VERSION 5.7 ;
  NOWIREEXTENSIONATPIN ON ;
  DIVIDERCHAR "/" ;
  BUSBITCHARS "[]" ;
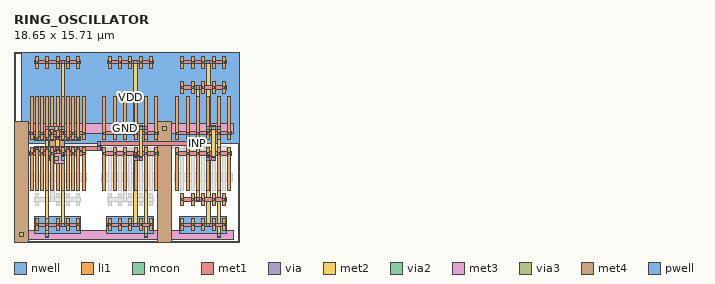
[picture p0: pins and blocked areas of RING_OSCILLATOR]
MACRO RING_OSCILLATOR
  CLASS BLOCK ;
  FOREIGN RING_OSCILLATOR ;
  ORIGIN 0.000 0.000 ;
  SIZE 18.650 BY 15.710 ;
  PIN VDD
    ANTENNADIFFAREA 7.014000 ;
    PORT
      LAYER nwell ;
        RECT 0.590 8.150 18.650 15.710 ;
      LAYER li1 ;
        RECT 1.755 14.365 2.005 15.375 ;
        RECT 2.615 14.365 2.865 15.375 ;
        RECT 3.475 14.365 3.725 15.375 ;
        RECT 4.335 14.365 4.585 15.375 ;
        RECT 5.195 14.365 5.445 15.375 ;
        RECT 7.775 14.365 8.025 15.375 ;
        RECT 8.635 14.365 8.885 15.375 ;
        RECT 9.495 14.365 9.745 15.375 ;
        RECT 10.355 14.365 10.605 15.375 ;
        RECT 11.215 14.365 11.465 15.375 ;
        RECT 13.795 14.365 14.045 15.375 ;
        RECT 14.655 14.365 14.905 15.375 ;
        RECT 15.515 14.365 15.765 15.375 ;
        RECT 16.375 14.365 16.625 15.375 ;
        RECT 17.235 14.365 17.485 15.375 ;
        RECT 1.325 8.485 1.575 12.015 ;
        RECT 2.185 8.485 2.435 12.015 ;
        RECT 3.045 8.485 3.295 12.015 ;
        RECT 3.905 8.485 4.155 12.015 ;
        RECT 4.765 8.485 5.015 12.015 ;
        RECT 5.625 8.485 5.875 12.015 ;
        RECT 7.345 8.485 7.595 12.015 ;
        RECT 8.205 8.485 8.455 12.015 ;
        RECT 9.065 8.485 9.315 12.015 ;
        RECT 9.925 8.485 10.175 12.015 ;
        RECT 10.785 8.485 11.035 12.015 ;
        RECT 11.645 8.485 11.895 12.015 ;
        RECT 13.365 8.485 13.615 12.015 ;
        RECT 14.225 8.485 14.475 12.015 ;
        RECT 15.085 8.485 15.335 12.015 ;
        RECT 15.945 8.485 16.195 12.015 ;
        RECT 16.805 8.485 17.055 12.015 ;
        RECT 17.665 8.485 17.915 12.015 ;
      LAYER mcon ;
        RECT 1.795 14.785 1.965 14.955 ;
        RECT 2.655 14.785 2.825 14.955 ;
        RECT 3.515 14.785 3.685 14.955 ;
        RECT 4.375 14.785 4.545 14.955 ;
        RECT 5.235 14.785 5.405 14.955 ;
        RECT 7.815 14.785 7.985 14.955 ;
        RECT 8.675 14.785 8.845 14.955 ;
        RECT 9.535 14.785 9.705 14.955 ;
        RECT 10.395 14.785 10.565 14.955 ;
        RECT 11.255 14.785 11.425 14.955 ;
        RECT 13.835 14.785 14.005 14.955 ;
        RECT 14.695 14.785 14.865 14.955 ;
        RECT 15.555 14.785 15.725 14.955 ;
        RECT 16.415 14.785 16.585 14.955 ;
        RECT 17.275 14.785 17.445 14.955 ;
        RECT 1.365 8.905 1.535 9.075 ;
        RECT 2.225 8.905 2.395 9.075 ;
        RECT 3.085 8.905 3.255 9.075 ;
        RECT 3.945 8.905 4.115 9.075 ;
        RECT 4.805 8.905 4.975 9.075 ;
        RECT 5.665 8.905 5.835 9.075 ;
        RECT 7.385 8.905 7.555 9.075 ;
        RECT 8.245 8.905 8.415 9.075 ;
        RECT 9.105 8.905 9.275 9.075 ;
        RECT 9.965 8.905 10.135 9.075 ;
        RECT 10.825 8.905 10.995 9.075 ;
        RECT 11.685 8.905 11.855 9.075 ;
        RECT 13.405 8.905 13.575 9.075 ;
        RECT 14.265 8.905 14.435 9.075 ;
        RECT 15.125 8.905 15.295 9.075 ;
        RECT 15.985 8.905 16.155 9.075 ;
        RECT 16.845 8.905 17.015 9.075 ;
        RECT 17.705 8.905 17.875 9.075 ;
      LAYER met1 ;
        RECT 1.710 14.730 5.490 15.010 ;
        RECT 7.730 14.730 11.510 15.010 ;
        RECT 13.750 14.730 17.530 15.010 ;
        RECT 2.580 9.270 4.190 9.550 ;
        RECT 9.890 9.270 11.070 9.550 ;
        RECT 15.910 9.270 17.090 9.550 ;
        RECT 1.280 8.850 5.920 9.130 ;
        RECT 7.300 8.850 11.940 9.130 ;
        RECT 13.320 8.850 17.960 9.130 ;
      LAYER via ;
        RECT 3.900 14.740 4.160 15.000 ;
        RECT 9.920 14.740 10.180 15.000 ;
        RECT 15.940 14.740 16.200 15.000 ;
        RECT 2.610 9.280 2.870 9.540 ;
        RECT 3.900 9.280 4.160 9.540 ;
        RECT 9.920 9.280 10.180 9.540 ;
        RECT 10.780 9.280 11.040 9.540 ;
        RECT 15.940 9.280 16.200 9.540 ;
        RECT 16.800 9.280 17.060 9.540 ;
        RECT 3.900 8.860 4.160 9.120 ;
        RECT 9.920 8.860 10.180 9.120 ;
        RECT 15.940 8.860 16.200 9.120 ;
      LAYER met2 ;
        RECT 2.600 0.405 2.880 9.570 ;
        RECT 3.890 8.830 4.170 15.030 ;
        RECT 9.910 8.830 10.190 15.030 ;
        RECT 10.770 0.405 11.050 9.570 ;
        RECT 15.930 8.830 16.210 15.030 ;
        RECT 16.790 0.405 17.070 9.570 ;
      LAYER via2 ;
        RECT 2.600 0.450 2.880 0.730 ;
        RECT 10.770 0.450 11.050 0.730 ;
        RECT 16.790 0.450 17.070 0.730 ;
      LAYER met3 ;
        RECT 0.190 0.190 18.190 0.990 ;
      LAYER via3 ;
        RECT 0.430 0.430 0.750 0.750 ;
      LAYER met4 ;
        RECT 0.000 0.000 1.180 10.000 ;
    END
  END VDD
  PIN INP
    ANTENNAGATEAREA 1.890000 ;
    ANTENNADIFFAREA 1.764000 ;
    PORT
      LAYER li1 ;
        RECT 13.795 12.265 14.045 13.275 ;
        RECT 14.655 12.265 14.905 13.275 ;
        RECT 15.515 12.265 15.765 13.275 ;
        RECT 16.375 12.265 16.625 13.275 ;
        RECT 17.235 12.265 17.485 13.275 ;
        RECT 1.755 8.485 2.005 12.015 ;
        RECT 2.615 8.485 2.865 12.015 ;
        RECT 3.475 8.485 3.725 12.015 ;
        RECT 4.335 8.485 4.585 12.015 ;
        RECT 5.195 8.485 5.445 12.015 ;
        RECT 1.755 4.285 2.005 7.815 ;
        RECT 2.615 4.285 2.865 7.815 ;
        RECT 3.475 4.285 3.725 7.815 ;
        RECT 4.335 4.285 4.585 7.815 ;
        RECT 5.195 4.285 5.445 7.815 ;
        RECT 13.795 3.025 14.045 4.035 ;
        RECT 14.655 3.025 14.905 4.035 ;
        RECT 15.515 3.025 15.765 4.035 ;
        RECT 16.375 3.025 16.625 4.035 ;
        RECT 17.235 3.025 17.485 4.035 ;
      LAYER mcon ;
        RECT 13.835 12.685 14.005 12.855 ;
        RECT 14.695 12.685 14.865 12.855 ;
        RECT 15.555 12.685 15.725 12.855 ;
        RECT 16.415 12.685 16.585 12.855 ;
        RECT 17.275 12.685 17.445 12.855 ;
        RECT 1.795 8.485 1.965 8.655 ;
        RECT 2.655 8.485 2.825 8.655 ;
        RECT 3.515 8.485 3.685 8.655 ;
        RECT 4.375 8.485 4.545 8.655 ;
        RECT 5.235 8.485 5.405 8.655 ;
        RECT 1.795 7.645 1.965 7.815 ;
        RECT 2.655 7.645 2.825 7.815 ;
        RECT 3.515 7.645 3.685 7.815 ;
        RECT 4.375 7.645 4.545 7.815 ;
        RECT 5.235 7.645 5.405 7.815 ;
        RECT 13.835 3.445 14.005 3.615 ;
        RECT 14.695 3.445 14.865 3.615 ;
        RECT 15.555 3.445 15.725 3.615 ;
        RECT 16.415 3.445 16.585 3.615 ;
        RECT 17.275 3.445 17.445 3.615 ;
      LAYER met1 ;
        RECT 13.750 12.630 17.530 12.910 ;
        RECT 1.710 8.430 5.490 8.710 ;
        RECT 6.880 8.010 15.370 8.290 ;
        RECT 1.710 7.590 7.200 7.870 ;
        RECT 13.750 3.390 17.530 3.670 ;
      LAYER via ;
        RECT 15.080 12.640 15.340 12.900 ;
        RECT 3.470 8.440 3.730 8.700 ;
        RECT 6.910 8.020 7.170 8.280 ;
        RECT 15.080 8.020 15.340 8.280 ;
        RECT 3.470 7.600 3.730 7.860 ;
        RECT 6.910 7.600 7.170 7.860 ;
        RECT 15.080 3.400 15.340 3.660 ;
      LAYER met2 ;
        RECT 3.460 7.570 3.740 8.730 ;
        RECT 6.900 7.570 7.180 8.310 ;
        RECT 15.070 3.370 15.350 12.930 ;
    END
  END INP
  PIN GND
    ANTENNADIFFAREA 4.935000 ;
    PORT
      LAYER pwell ;
        RECT 1.665 0.740 5.535 2.120 ;
        RECT 7.685 0.740 11.555 2.120 ;
        RECT 13.705 0.740 17.575 2.120 ;
      LAYER li1 ;
        RECT 1.325 4.285 1.575 7.815 ;
        RECT 2.185 4.285 2.435 7.815 ;
        RECT 3.045 4.285 3.295 7.815 ;
        RECT 3.905 4.285 4.155 7.815 ;
        RECT 4.765 4.285 5.015 7.815 ;
        RECT 5.625 4.285 5.875 7.815 ;
        RECT 7.345 4.285 7.595 7.815 ;
        RECT 8.205 4.285 8.455 7.815 ;
        RECT 9.065 4.285 9.315 7.815 ;
        RECT 9.925 4.285 10.175 7.815 ;
        RECT 10.785 4.285 11.035 7.815 ;
        RECT 11.645 4.285 11.895 7.815 ;
        RECT 13.365 4.285 13.615 7.815 ;
        RECT 14.225 4.285 14.475 7.815 ;
        RECT 15.085 4.285 15.335 7.815 ;
        RECT 15.945 4.285 16.195 7.815 ;
        RECT 16.805 4.285 17.055 7.815 ;
        RECT 17.665 4.285 17.915 7.815 ;
        RECT 1.755 0.925 2.005 1.935 ;
        RECT 2.615 0.925 2.865 1.935 ;
        RECT 3.475 0.925 3.725 1.935 ;
        RECT 4.335 0.925 4.585 1.935 ;
        RECT 5.195 0.925 5.445 1.935 ;
        RECT 7.775 0.925 8.025 1.935 ;
        RECT 8.635 0.925 8.885 1.935 ;
        RECT 9.495 0.925 9.745 1.935 ;
        RECT 10.355 0.925 10.605 1.935 ;
        RECT 11.215 0.925 11.465 1.935 ;
        RECT 13.795 0.925 14.045 1.935 ;
        RECT 14.655 0.925 14.905 1.935 ;
        RECT 15.515 0.925 15.765 1.935 ;
        RECT 16.375 0.925 16.625 1.935 ;
        RECT 17.235 0.925 17.485 1.935 ;
      LAYER mcon ;
        RECT 1.365 7.225 1.535 7.395 ;
        RECT 2.225 7.225 2.395 7.395 ;
        RECT 3.085 7.225 3.255 7.395 ;
        RECT 3.945 7.225 4.115 7.395 ;
        RECT 4.805 7.225 4.975 7.395 ;
        RECT 5.665 7.225 5.835 7.395 ;
        RECT 7.385 7.225 7.555 7.395 ;
        RECT 8.245 7.225 8.415 7.395 ;
        RECT 9.105 7.225 9.275 7.395 ;
        RECT 9.965 7.225 10.135 7.395 ;
        RECT 10.825 7.225 10.995 7.395 ;
        RECT 11.685 7.225 11.855 7.395 ;
        RECT 13.405 7.225 13.575 7.395 ;
        RECT 14.265 7.225 14.435 7.395 ;
        RECT 15.125 7.225 15.295 7.395 ;
        RECT 15.985 7.225 16.155 7.395 ;
        RECT 16.845 7.225 17.015 7.395 ;
        RECT 17.705 7.225 17.875 7.395 ;
        RECT 1.795 1.345 1.965 1.515 ;
        RECT 2.655 1.345 2.825 1.515 ;
        RECT 3.515 1.345 3.685 1.515 ;
        RECT 4.375 1.345 4.545 1.515 ;
        RECT 5.235 1.345 5.405 1.515 ;
        RECT 7.815 1.345 7.985 1.515 ;
        RECT 8.675 1.345 8.845 1.515 ;
        RECT 9.535 1.345 9.705 1.515 ;
        RECT 10.395 1.345 10.565 1.515 ;
        RECT 11.255 1.345 11.425 1.515 ;
        RECT 13.835 1.345 14.005 1.515 ;
        RECT 14.695 1.345 14.865 1.515 ;
        RECT 15.555 1.345 15.725 1.515 ;
        RECT 16.415 1.345 16.585 1.515 ;
        RECT 17.275 1.345 17.445 1.515 ;
      LAYER met1 ;
        RECT 1.280 7.170 5.920 7.450 ;
        RECT 7.300 7.170 11.940 7.450 ;
        RECT 13.320 7.170 17.960 7.450 ;
        RECT 9.890 6.750 10.640 7.030 ;
        RECT 15.910 6.750 16.660 7.030 ;
        RECT 1.710 1.290 5.490 1.570 ;
        RECT 7.730 1.290 11.510 1.570 ;
        RECT 13.750 1.290 17.530 1.570 ;
      LAYER via ;
        RECT 3.900 7.180 4.160 7.440 ;
        RECT 9.920 7.180 10.180 7.440 ;
        RECT 15.940 7.180 16.200 7.440 ;
        RECT 9.920 6.760 10.180 7.020 ;
        RECT 10.350 6.760 10.610 7.020 ;
        RECT 15.940 6.760 16.200 7.020 ;
        RECT 16.370 6.760 16.630 7.020 ;
        RECT 3.900 1.300 4.160 1.560 ;
        RECT 9.920 1.300 10.180 1.560 ;
        RECT 15.940 1.300 16.200 1.560 ;
      LAYER met2 ;
        RECT 3.890 1.270 4.170 7.470 ;
        RECT 9.910 1.270 10.190 7.470 ;
        RECT 10.340 6.730 10.620 9.595 ;
        RECT 15.930 1.270 16.210 7.470 ;
        RECT 16.360 6.730 16.640 9.595 ;
      LAYER via2 ;
        RECT 10.340 9.270 10.620 9.550 ;
        RECT 3.890 6.750 4.170 7.030 ;
        RECT 16.360 9.270 16.640 9.550 ;
      LAYER met3 ;
        RECT 0.190 9.010 18.190 9.810 ;
        RECT 3.385 6.490 4.195 7.290 ;
      LAYER via3 ;
        RECT 3.390 9.250 3.710 9.570 ;
        RECT 12.270 9.250 12.590 9.570 ;
        RECT 3.390 6.730 3.710 7.050 ;
      LAYER met4 ;
        RECT 2.960 6.725 4.140 9.575 ;
        RECT 11.840 0.000 13.020 10.000 ;
    END
  END GND
  OBS
      LAYER pwell ;
        RECT 1.195 4.975 6.005 5.655 ;
        RECT 7.215 4.975 12.025 5.655 ;
        RECT 13.235 4.975 18.045 5.655 ;
      LAYER li1 ;
        RECT 1.755 12.265 2.005 13.275 ;
        RECT 2.615 12.265 2.865 13.275 ;
        RECT 3.475 12.265 3.725 13.275 ;
        RECT 4.335 12.265 4.585 13.275 ;
        RECT 5.195 12.265 5.445 13.275 ;
        RECT 7.775 12.265 8.025 13.275 ;
        RECT 8.635 12.265 8.885 13.275 ;
        RECT 9.495 12.265 9.745 13.275 ;
        RECT 10.355 12.265 10.605 13.275 ;
        RECT 11.215 12.265 11.465 13.275 ;
        RECT 7.775 8.485 8.025 12.015 ;
        RECT 8.635 8.485 8.885 12.015 ;
        RECT 9.495 8.485 9.745 12.015 ;
        RECT 10.355 8.485 10.605 12.015 ;
        RECT 11.215 8.485 11.465 12.015 ;
        RECT 13.795 8.485 14.045 12.015 ;
        RECT 14.655 8.485 14.905 12.015 ;
        RECT 15.515 8.485 15.765 12.015 ;
        RECT 16.375 8.485 16.625 12.015 ;
        RECT 17.235 8.485 17.485 12.015 ;
        RECT 7.775 4.285 8.025 7.815 ;
        RECT 8.635 4.285 8.885 7.815 ;
        RECT 9.495 4.285 9.745 7.815 ;
        RECT 10.355 4.285 10.605 7.815 ;
        RECT 11.215 4.285 11.465 7.815 ;
        RECT 13.795 4.285 14.045 7.815 ;
        RECT 14.655 4.285 14.905 7.815 ;
        RECT 15.515 4.285 15.765 7.815 ;
        RECT 16.375 4.285 16.625 7.815 ;
        RECT 17.235 4.285 17.485 7.815 ;
        RECT 1.755 3.025 2.005 4.035 ;
        RECT 2.615 3.025 2.865 4.035 ;
        RECT 3.475 3.025 3.725 4.035 ;
        RECT 4.335 3.025 4.585 4.035 ;
        RECT 5.195 3.025 5.445 4.035 ;
        RECT 7.775 3.025 8.025 4.035 ;
        RECT 8.635 3.025 8.885 4.035 ;
        RECT 9.495 3.025 9.745 4.035 ;
        RECT 10.355 3.025 10.605 4.035 ;
        RECT 11.215 3.025 11.465 4.035 ;
      LAYER mcon ;
        RECT 1.795 12.685 1.965 12.855 ;
        RECT 2.655 12.685 2.825 12.855 ;
        RECT 3.515 12.685 3.685 12.855 ;
        RECT 4.375 12.685 4.545 12.855 ;
        RECT 5.235 12.685 5.405 12.855 ;
        RECT 7.815 12.685 7.985 12.855 ;
        RECT 8.675 12.685 8.845 12.855 ;
        RECT 9.535 12.685 9.705 12.855 ;
        RECT 10.395 12.685 10.565 12.855 ;
        RECT 11.255 12.685 11.425 12.855 ;
        RECT 7.815 8.485 7.985 8.655 ;
        RECT 8.675 8.485 8.845 8.655 ;
        RECT 9.535 8.485 9.705 8.655 ;
        RECT 10.395 8.485 10.565 8.655 ;
        RECT 11.255 8.485 11.425 8.655 ;
        RECT 13.835 8.485 14.005 8.655 ;
        RECT 14.695 8.485 14.865 8.655 ;
        RECT 15.555 8.485 15.725 8.655 ;
        RECT 16.415 8.485 16.585 8.655 ;
        RECT 17.275 8.485 17.445 8.655 ;
        RECT 7.815 7.645 7.985 7.815 ;
        RECT 8.675 7.645 8.845 7.815 ;
        RECT 9.535 7.645 9.705 7.815 ;
        RECT 10.395 7.645 10.565 7.815 ;
        RECT 11.255 7.645 11.425 7.815 ;
        RECT 13.835 7.645 14.005 7.815 ;
        RECT 14.695 7.645 14.865 7.815 ;
        RECT 15.555 7.645 15.725 7.815 ;
        RECT 16.415 7.645 16.585 7.815 ;
        RECT 17.275 7.645 17.445 7.815 ;
        RECT 1.795 3.445 1.965 3.615 ;
        RECT 2.655 3.445 2.825 3.615 ;
        RECT 3.515 3.445 3.685 3.615 ;
        RECT 4.375 3.445 4.545 3.615 ;
        RECT 5.235 3.445 5.405 3.615 ;
        RECT 7.815 3.445 7.985 3.615 ;
        RECT 8.675 3.445 8.845 3.615 ;
        RECT 9.535 3.445 9.705 3.615 ;
        RECT 10.395 3.445 10.565 3.615 ;
        RECT 11.255 3.445 11.425 3.615 ;
      LAYER met1 ;
        RECT 1.710 12.630 5.490 12.910 ;
        RECT 7.730 12.630 11.510 12.910 ;
        RECT 7.730 8.430 11.510 8.710 ;
        RECT 13.750 8.430 17.530 8.710 ;
        RECT 7.730 7.590 11.510 7.870 ;
        RECT 13.750 7.590 17.530 7.870 ;
        RECT 1.710 3.390 5.490 3.670 ;
        RECT 7.730 3.390 11.510 3.670 ;
      LAYER via ;
        RECT 3.040 12.640 3.300 12.900 ;
        RECT 9.060 12.640 9.320 12.900 ;
        RECT 9.490 8.440 9.750 8.700 ;
        RECT 15.510 8.440 15.770 8.700 ;
        RECT 7.770 7.600 8.030 7.860 ;
        RECT 9.490 7.600 9.750 7.860 ;
        RECT 13.790 7.600 14.050 7.860 ;
        RECT 15.510 7.600 15.770 7.860 ;
        RECT 3.040 3.400 3.300 3.660 ;
        RECT 9.060 3.400 9.320 3.660 ;
      LAYER met2 ;
        RECT 3.030 3.370 3.310 12.930 ;
        RECT 7.760 7.570 8.040 8.335 ;
        RECT 9.050 3.370 9.330 12.930 ;
        RECT 9.480 7.570 9.760 8.730 ;
        RECT 13.780 7.570 14.060 8.335 ;
        RECT 15.500 7.570 15.780 8.730 ;
      LAYER via2 ;
        RECT 3.030 8.010 3.310 8.290 ;
        RECT 7.760 8.010 8.040 8.290 ;
        RECT 9.050 8.010 9.330 8.290 ;
        RECT 13.780 8.010 14.060 8.290 ;
      LAYER met3 ;
        RECT 3.005 7.750 8.065 8.550 ;
        RECT 9.025 7.750 14.085 8.550 ;
  END
END RING_OSCILLATOR
END LIBRARY

